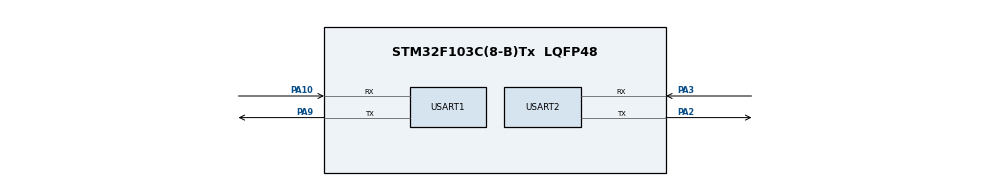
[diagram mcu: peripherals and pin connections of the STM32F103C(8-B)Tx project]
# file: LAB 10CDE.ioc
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Mcu.Family=STM32F1
Mcu.Name=STM32F103C(8-B)Tx
Mcu.Package=LQFP48
NVIC.PriorityGroup=NVIC_PRIORITYGROUP_4
PA10.Mode=Asynchronous
PA10.Signal=USART1_RX
PA13.Mode=Serial_Wire
PA13.Signal=SYS_JTMS-SWDIO
PA14.Mode=Serial_Wire
PA14.Signal=SYS_JTCK-SWCLK
PA2.Mode=Asynchronous
PA2.Signal=USART2_TX
PA3.Mode=Asynchronous
PA3.Signal=USART2_RX
PA9.Mode=Asynchronous
PA9.Signal=USART1_TX
PD0-OSC_IN.Mode=HSE-External-Oscillator
PD0-OSC_IN.Signal=RCC_OSC_IN
PD1-OSC_OUT.Mode=HSE-External-Oscillator
PD1-OSC_OUT.Signal=RCC_OSC_OUT
ProjectManager.HeapSize=0x200
ProjectManager.StackSize=0x400
ProjectManager.TargetToolchain=MDK-ARM V5.32
RCC.AHBFreq_Value=72000000
RCC.APB1CLKDivider=RCC_HCLK_DIV2
RCC.APB1Freq_Value=36000000
RCC.APB1TimFreq_Value=72000000
RCC.APB2Freq_Value=72000000
RCC.APB2TimFreq_Value=72000000
RCC.HCLKFreq_Value=72000000
RCC.PLLMUL=RCC_PLL_MUL9
RCC.PLLSourceVirtual=RCC_PLLSOURCE_HSE
RCC.SYSCLKFreq_VALUE=72000000
RCC.SYSCLKSource=RCC_SYSCLKSOURCE_PLLCLK
RCC.USBFreq_Value=72000000
USART1.VirtualMode=VM_ASYNC
USART2.VirtualMode=VM_ASYNC
board=custom

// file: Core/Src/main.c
/* USER CODE BEGIN Header */
/**
  ******************************************************************************
  * @file           : main.c
  * @brief          : Main program body
  ******************************************************************************
  * @attention
  *
  * Copyright (c) 2026 STMicroelectronics.
  * All rights reserved.
  *
  * This software is licensed under terms that can be found in the LICENSE file
  * in the root directory of this software component.
  * If no LICENSE file comes with this software, it is provided AS-IS.
  *
  ******************************************************************************
  */
/* USER CODE END Header */
#include "main.h"

#include "string.h"

UART_HandleTypeDef huart1;
UART_HandleTypeDef huart2;

void SystemClock_Config(void);
static void MX_GPIO_Init(void);
static void MX_USART1_UART_Init(void);
static void MX_USART2_UART_Init(void);

int main(void)
{

  /* MCU Configuration--------------------------------------------------------*/

  /* Reset of all peripherals, Initializes the Flash interface and the Systick. */
  HAL_Init();

  /* Configure the system clock */
  SystemClock_Config();

  /* Initialize all configured peripherals */
  MX_GPIO_Init();
  MX_USART1_UART_Init();
  MX_USART2_UART_Init();
  /* USER CODE BEGIN 2 */
	uint8_t rx[256];

    char command1[] = "AT\r\n";

    HAL_UART_Transmit(&huart1, (uint8_t *)command1, strlen(command1),HAL_MAX_DELAY);

    while (HAL_UART_Receive(&huart1, rx, 1, 2000) == HAL_OK)
    {
        HAL_UART_Transmit(&huart2, rx, 1, HAL_MAX_DELAY);
    }

    HAL_Delay(2000);

		char cmd2[] = "AT+CWMODE=1\r\n";
		memset(rx,0,sizeof(rx));

		HAL_UART_Transmit(&huart1, (uint8_t *)cmd2, strlen(cmd2),HAL_MAX_DELAY);

    while (HAL_UART_Receive(&huart1, rx, 1, 2000) == HAL_OK)
    {
        HAL_UART_Transmit(&huart2, rx, 1, HAL_MAX_DELAY);
    }

    HAL_Delay(2000);

		uint8_t cmd3[] = "AT+CWJAP=\"SNUC\",\"snu12345\"\r\n";
		uint16_t rxLen;

		HAL_UART_Transmit(&huart1, cmd3, sizeof(cmd3)-1,2000);

    HAL_UARTEx_ReceiveToIdle(&huart1,rx,sizeof(rx),&rxLen,5000);

		HAL_UART_Transmit(&huart2,rx,rxLen,2000);

		HAL_Delay(5000);

	uint8_t cmd6[] = "AT+CIFSR\r\n";
	HAL_UART_Transmit(&huart1,cmd6,sizeof(cmd6) -1,2000);

	HAL_UARTEx_ReceiveToIdle(&huart1,rx,sizeof(rx),&rxLen,5000);

	HAL_UART_Transmit(&huart2,rx,rxLen,2000);

	HAL_Delay(1000);

/* USER CODE END 2 */

  /* Infinite loop */
  while (1)
  {

  }
}

void SystemClock_Config(void)
{
  RCC_OscInitTypeDef RCC_OscInitStruct = {0};
  RCC_ClkInitTypeDef RCC_ClkInitStruct = {0};

  /** Initializes the RCC Oscillators according to the specified parameters
  * in the RCC_OscInitTypeDef structure.
  */
  RCC_OscInitStruct.OscillatorType = RCC_OSCILLATORTYPE_HSE;
  RCC_OscInitStruct.HSEState = RCC_HSE_ON;
  RCC_OscInitStruct.HSEPredivValue = RCC_HSE_PREDIV_DIV1;
  RCC_OscInitStruct.HSIState = RCC_HSI_ON;
  RCC_OscInitStruct.PLL.PLLState = RCC_PLL_ON;
  RCC_OscInitStruct.PLL.PLLSource = RCC_PLLSOURCE_HSE;
  RCC_OscInitStruct.PLL.PLLMUL = RCC_PLL_MUL2;
  if (HAL_RCC_OscConfig(&RCC_OscInitStruct) != HAL_OK)
  {
    Error_Handler();
  }

  /** Initializes the CPU, AHB and APB buses clocks
  */
  RCC_ClkInitStruct.ClockType = RCC_CLOCKTYPE_HCLK|RCC_CLOCKTYPE_SYSCLK
                              |RCC_CLOCKTYPE_PCLK1|RCC_CLOCKTYPE_PCLK2;
  RCC_ClkInitStruct.SYSCLKSource = RCC_SYSCLKSOURCE_PLLCLK;
  RCC_ClkInitStruct.AHBCLKDivider = RCC_SYSCLK_DIV1;
  RCC_ClkInitStruct.APB1CLKDivider = RCC_HCLK_DIV1;
  RCC_ClkInitStruct.APB2CLKDivider = RCC_HCLK_DIV1;

  if (HAL_RCC_ClockConfig(&RCC_ClkInitStruct, FLASH_LATENCY_0) != HAL_OK)
  {
    Error_Handler();
  }
}

static void MX_USART1_UART_Init(void)
{

  huart1.Instance = USART1;
  huart1.Init.BaudRate = 115200;
  huart1.Init.WordLength = UART_WORDLENGTH_8B;
  huart1.Init.StopBits = UART_STOPBITS_1;
  huart1.Init.Parity = UART_PARITY_NONE;
  huart1.Init.Mode = UART_MODE_TX_RX;
  huart1.Init.HwFlowCtl = UART_HWCONTROL_NONE;
  huart1.Init.OverSampling = UART_OVERSAMPLING_16;
  if (HAL_UART_Init(&huart1) != HAL_OK)
  {
    Error_Handler();
  }

}

static void MX_USART2_UART_Init(void)
{

  huart2.Instance = USART2;
  huart2.Init.BaudRate = 115200;
  huart2.Init.WordLength = UART_WORDLENGTH_8B;
  huart2.Init.StopBits = UART_STOPBITS_1;
  huart2.Init.Parity = UART_PARITY_NONE;
  huart2.Init.Mode = UART_MODE_TX_RX;
  huart2.Init.HwFlowCtl = UART_HWCONTROL_NONE;
  huart2.Init.OverSampling = UART_OVERSAMPLING_16;
  if (HAL_UART_Init(&huart2) != HAL_OK)
  {
    Error_Handler();
  }

}

static void MX_GPIO_Init(void)
{

  /* GPIO Ports Clock Enable */
  __HAL_RCC_GPIOD_CLK_ENABLE();
  __HAL_RCC_GPIOA_CLK_ENABLE();

}

void Error_Handler(void)
{
  __disable_irq();
  while (1)
  {
  }
}
